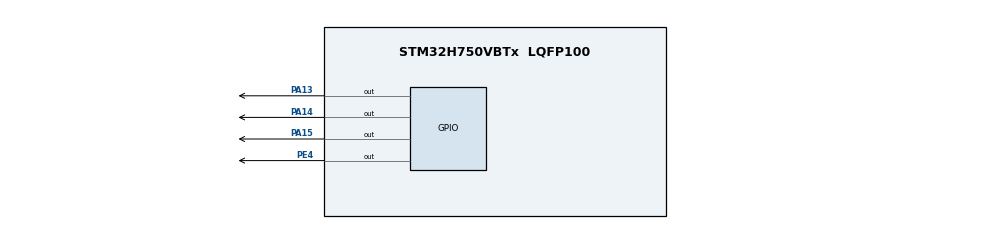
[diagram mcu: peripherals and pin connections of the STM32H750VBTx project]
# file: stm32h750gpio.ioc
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CORTEX_M7.default_mode_Activation=1
Mcu.Family=STM32H7
Mcu.Name=STM32H750VBTx
Mcu.Package=LQFP100
NVIC.PriorityGroup=NVIC_PRIORITYGROUP_4
PA13\ (JTMS/SWDIO).Signal=GPIO_Output
PA14\ (JTCK/SWCLK).Signal=GPIO_Output
PA15\ (JTDI).Signal=GPIO_Output
PE4.Signal=GPIO_Output
ProjectManager.HeapSize=0x200
ProjectManager.StackSize=0x400
ProjectManager.TargetToolchain=Makefile
RCC.ADCFreq_Value=129000000
RCC.APB1Freq_Value=64000000
RCC.APB2Freq_Value=64000000
RCC.APB3Freq_Value=64000000
RCC.APB4Freq_Value=64000000
RCC.CortexFreq_Value=64000000
RCC.HCLKFreq_Value=64000000
RCC.SYSCLKFreq_VALUE=64000000
RCC.USBFreq_Value=129000000
VP_MEMORYMAP_VS_MEMORYMAP.Mode=CurAppReg
board=custom

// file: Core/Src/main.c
/* USER CODE BEGIN Header */
/**
  ******************************************************************************
  * @file           : main.c
  * @brief          : Main program body
  ******************************************************************************
  * @attention
  *
  * Copyright (c) 2026 STMicroelectronics.
  * All rights reserved.
  *
  * This software is licensed under terms that can be found in the LICENSE file
  * in the root directory of this software component.
  * If no LICENSE file comes with this software, it is provided AS-IS.
  *
  ******************************************************************************
  */
/* USER CODE END Header */
#include "main.h"

void SystemClock_Config(void);
static void MPU_Config(void);
static void MX_GPIO_Init(void);

/*
// Quick and dirty delay
static void delay (unsigned int time) {
    for (unsigned int i = 0; i < time; i++)
        for (volatile unsigned int j = 0; j < 2000; j++);
}
*/
int main(void)
{
  static GPIO_InitTypeDef  GPIO_InitStruct;

  /* MPU Configuration--------------------------------------------------------*/
  MPU_Config();

  /* MCU Configuration--------------------------------------------------------*/

  /* Reset of all peripherals, Initializes the Flash interface and the Systick. */
  HAL_Init();

  /* Configure the system clock */
  SystemClock_Config();

#if 0 //test GPIOD GPIO_PIN_10 //This works.
  /* -1- Enable GPIO Clock (to be able to program the configuration registers) */
  __HAL_RCC_GPIOD_CLK_ENABLE();

  /* -2- Configure IO in output push-pull mode to drive external LEDs */
  GPIO_InitStruct.Mode  = GPIO_MODE_OUTPUT_PP;
  GPIO_InitStruct.Pull  = GPIO_PULLUP;
  GPIO_InitStruct.Speed = GPIO_SPEED_FREQ_VERY_HIGH;

  GPIO_InitStruct.Pin = GPIO_PIN_10;
  HAL_GPIO_Init(GPIOD, &GPIO_InitStruct);

  /* -3- Toggle IO in an infinite loop */
  while (1)
  {
    // Reset the state of pin 10 to output low
    GPIOD->BSRR = GPIO_BSRR_BR10;
    // Set the state of pin 10 to output high
    GPIOD->BSRR = GPIO_BSRR_BS10;
    //HAL_GPIO_TogglePin(GPIOD, GPIO_PIN_10);
    /* Insert delay 100 ms */
    //HAL_Delay(10);
  }
#else //toggle GPIOA pin 15, 10, 11

  /* Initialize all configured peripherals */
  MX_GPIO_Init();

  /* Infinite loop */
  /* USER CODE BEGIN WHILE */
  while (1)
  {
      // Reset the state of pin to output low
      GPIOA->BSRR = GPIO_BSRR_BR15| GPIO_BSRR_BR10 | GPIO_BSRR_BR11;
      //    GPIOE->BSRR = GPIO_BSRR_BR4;

      HAL_Delay(500);

      // Set the state of pin to output high
      GPIOA->BSRR = GPIO_BSRR_BS15 | GPIO_BSRR_BS10 | GPIO_BSRR_BS11;
      //    GPIOE->BSRR = GPIO_BSRR_BS4;

      HAL_Delay(500);
  }
#endif
}

void SystemClock_Config(void)
{
  RCC_OscInitTypeDef RCC_OscInitStruct = {0};
  RCC_ClkInitTypeDef RCC_ClkInitStruct = {0};

  /** Supply configuration update enable
  */
  HAL_PWREx_ConfigSupply(PWR_LDO_SUPPLY);

  /** Configure the main internal regulator output voltage
  */
  __HAL_PWR_VOLTAGESCALING_CONFIG(PWR_REGULATOR_VOLTAGE_SCALE3);

  while(!__HAL_PWR_GET_FLAG(PWR_FLAG_VOSRDY)) {}

  /** Initializes the RCC Oscillators according to the specified parameters
  * in the RCC_OscInitTypeDef structure.
  */
  RCC_OscInitStruct.OscillatorType = RCC_OSCILLATORTYPE_HSI;
  RCC_OscInitStruct.HSIState = RCC_HSI_DIV1;
  RCC_OscInitStruct.HSICalibrationValue = RCC_HSICALIBRATION_DEFAULT;
  RCC_OscInitStruct.PLL.PLLState = RCC_PLL_NONE;
  if (HAL_RCC_OscConfig(&RCC_OscInitStruct) != HAL_OK)
  {
    Error_Handler();
  }

  /** Initializes the CPU, AHB and APB buses clocks
  */
  RCC_ClkInitStruct.ClockType = RCC_CLOCKTYPE_HCLK|RCC_CLOCKTYPE_SYSCLK
                              |RCC_CLOCKTYPE_PCLK1|RCC_CLOCKTYPE_PCLK2
                              |RCC_CLOCKTYPE_D3PCLK1|RCC_CLOCKTYPE_D1PCLK1;
  RCC_ClkInitStruct.SYSCLKSource = RCC_SYSCLKSOURCE_HSI;
  RCC_ClkInitStruct.SYSCLKDivider = RCC_SYSCLK_DIV1;
  RCC_ClkInitStruct.AHBCLKDivider = RCC_HCLK_DIV1;
  RCC_ClkInitStruct.APB3CLKDivider = RCC_APB3_DIV1;
  RCC_ClkInitStruct.APB1CLKDivider = RCC_APB1_DIV1;
  RCC_ClkInitStruct.APB2CLKDivider = RCC_APB2_DIV1;
  RCC_ClkInitStruct.APB4CLKDivider = RCC_APB4_DIV1;

  if (HAL_RCC_ClockConfig(&RCC_ClkInitStruct, FLASH_LATENCY_1) != HAL_OK)
  {
    Error_Handler();
  }
}

static void MX_GPIO_Init(void)
{
  GPIO_InitTypeDef GPIO_InitStruct = {0};

  /* GPIO Ports Clock Enable */
  __HAL_RCC_GPIOE_CLK_ENABLE();
  __HAL_RCC_GPIOA_CLK_ENABLE();

  /*Configure GPIO pin Output Level */
  HAL_GPIO_WritePin(GPIOE, GPIO_PIN_4, GPIO_PIN_RESET);

  /*Configure GPIO pin Output Level */
  //HAL_GPIO_WritePin(GPIOA, GPIO_PIN_13|GPIO_PIN_14|GPIO_PIN_15, GPIO_PIN_RESET);
  HAL_GPIO_WritePin(GPIOA, GPIO_PIN_15, GPIO_PIN_RESET);

  /*Configure GPIO pin : PE4 */
  GPIO_InitStruct.Pin = GPIO_PIN_4;
  GPIO_InitStruct.Mode = GPIO_MODE_OUTPUT_PP;
  GPIO_InitStruct.Pull = GPIO_NOPULL;
  //GPIO_InitStruct.Speed = GPIO_SPEED_FREQ_LOW;
  GPIO_InitStruct.Speed = GPIO_SPEED_FREQ_HIGH;
  HAL_GPIO_Init(GPIOE, &GPIO_InitStruct);

  /*Configure GPIO pins : PA10 PA11 PA15 */
//  GPIO_InitStruct.Pin = GPIO_PIN_13|GPIO_PIN_14|GPIO_PIN_15;
  GPIO_InitStruct.Pin = GPIO_PIN_15 | GPIO_PIN_10 | GPIO_PIN_11;
  GPIO_InitStruct.Mode = GPIO_MODE_OUTPUT_PP;
  GPIO_InitStruct.Pull = GPIO_NOPULL;
  //GPIO_InitStruct.Speed = GPIO_SPEED_FREQ_LOW;
  GPIO_InitStruct.Speed = GPIO_SPEED_FREQ_HIGH;
  HAL_GPIO_Init(GPIOA, &GPIO_InitStruct);

}

 /* MPU Configuration */

void MPU_Config(void)
{
  MPU_Region_InitTypeDef MPU_InitStruct = {0};

  /* Disables the MPU */
  HAL_MPU_Disable();

  /** Initializes and configures the Region and the memory to be protected
  */
  MPU_InitStruct.Enable = MPU_REGION_ENABLE;
  MPU_InitStruct.Number = MPU_REGION_NUMBER0;
  MPU_InitStruct.BaseAddress = 0x0;
  MPU_InitStruct.Size = MPU_REGION_SIZE_4GB;
  MPU_InitStruct.SubRegionDisable = 0x87;
  MPU_InitStruct.TypeExtField = MPU_TEX_LEVEL0;
  MPU_InitStruct.AccessPermission = MPU_REGION_NO_ACCESS;
  MPU_InitStruct.DisableExec = MPU_INSTRUCTION_ACCESS_DISABLE;
  MPU_InitStruct.IsShareable = MPU_ACCESS_SHAREABLE;
  MPU_InitStruct.IsCacheable = MPU_ACCESS_NOT_CACHEABLE;
  MPU_InitStruct.IsBufferable = MPU_ACCESS_NOT_BUFFERABLE;

  HAL_MPU_ConfigRegion(&MPU_InitStruct);
  /* Enables the MPU */
  HAL_MPU_Enable(MPU_PRIVILEGED_DEFAULT);

}

void Error_Handler(void)
{
  __disable_irq();
  while (1)
  {
  }
}
